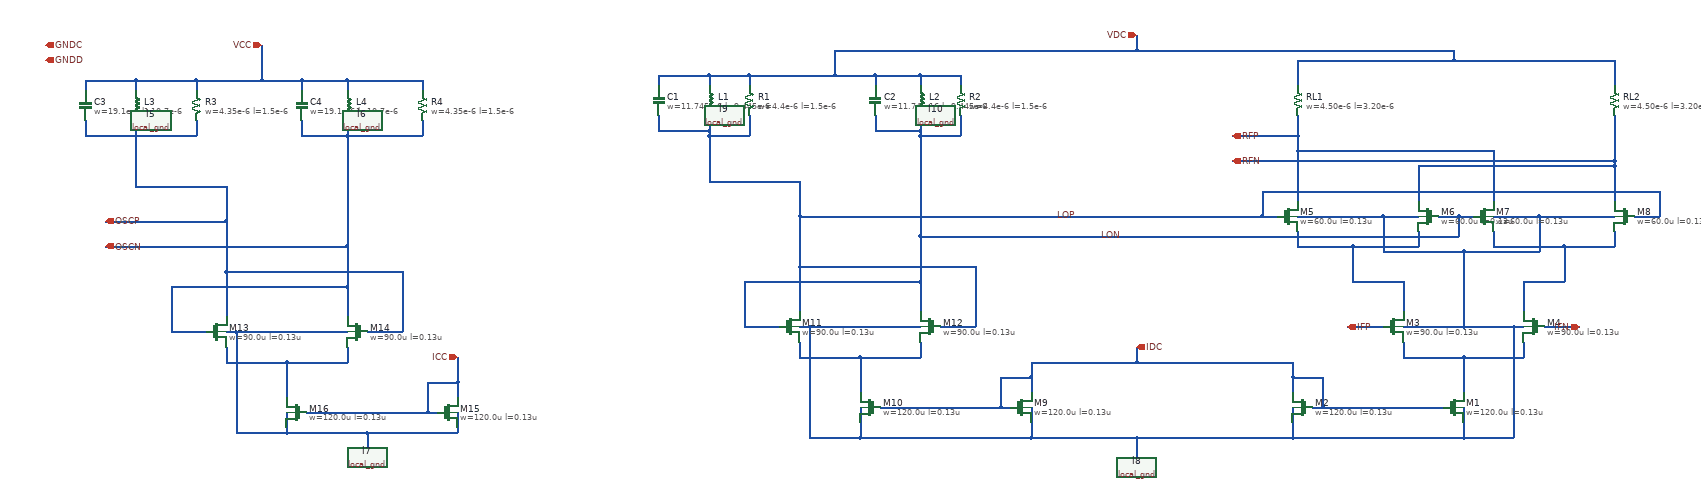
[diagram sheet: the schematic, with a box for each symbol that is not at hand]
v {xschem version=3.4.8RC file_version=1.3}
G {}
K {}
V {}
S {}
F {}
E {}
N 2820 -540 2820 -510 {
lab=#net1}
N 2940 -510 3060 -510 {
lab=#net1}
N 3060 -540 3060 -510 {
lab=#net1}
N 2940 -510 2940 -440 {
lab=#net1}
N 2820 -510 2940 -510 {
lab=#net1}
N 2660 -410 2900 -410 {
lab=IDC}
N 2600 -410 2600 -350 {
lab=GNDD}
N 2940 -410 2940 -350 {
lab=GNDD}
N 2600 -470 2600 -440 {
lab=IDC}
N 2600 -470 2660 -470 {
lab=IDC}
N 2600 -500 2600 -470 {
lab=IDC}
N 2660 -470 2660 -410 {
lab=IDC}
N 2640 -410 2660 -410 {
lab=IDC}
N 2710 -570 2780 -570 {
lab=IFP}
N 3100 -570 3170 -570 {
lab=IFN}
N 2610 -760 2610 -730 {
lab=#net2}
N 2720 -730 2850 -730 {
lab=#net2}
N 2850 -760 2850 -730 {
lab=#net2}
N 3000 -760 3000 -730 {
lab=#net3}
N 3140 -730 3240 -730 {
lab=#net3}
N 3240 -760 3240 -730 {
lab=#net3}
N 2820 -660 2820 -600 {
lab=#net2}
N 2720 -660 2820 -660 {
lab=#net2}
N 2720 -730 2720 -660 {
lab=#net2}
N 2610 -730 2720 -730 {
lab=#net2}
N 3060 -660 3060 -600 {
lab=#net3}
N 3060 -660 3140 -660 {
lab=#net3}
N 3140 -730 3140 -660 {
lab=#net3}
N 3000 -730 3140 -730 {
lab=#net3}
N 2930 -790 2960 -790 {
lab=LON}
N 3280 -790 3330 -790 {
lab=LOP}
N 3330 -840 3330 -790 {
lab=LOP}
N 2540 -840 3330 -840 {
lab=LOP}
N 2540 -840 2540 -790 {
lab=LOP}
N 2540 -790 2570 -790 {
lab=LOP}
N 2930 -790 2930 -750 {
lab=LON}
N 2890 -790 2930 -790 {
lab=LON}
N 2610 -920 2610 -820 {
lab=RFP}
N 3240 -890 3240 -820 {
lab=RFN}
N 2850 -890 3240 -890 {
lab=RFN}
N 3240 -900 3240 -890 {
lab=RFN}
N 3000 -920 3000 -820 {
lab=RFP}
N 2610 -920 3000 -920 {
lab=RFP}
N 2610 -950 2610 -920 {
lab=RFP}
N 2610 -1100 2610 -1050 {
lab=VDC}
N 2920 -1100 3240 -1100 {
lab=VDC}
N 3240 -1100 3240 -1050 {
lab=VDC}
N 2920 -1120 2920 -1100 {
lab=VDC}
N 2610 -1100 2920 -1100 {
lab=VDC}
N 2290 -350 2290 -310 {
lab=GNDD}
N 2600 -350 2940 -350 {
lab=GNDD}
N 3040 -570 3060 -570 {
lab=GNDD}
N 2780 -790 2850 -790 {
lab=GNDD}
N 3090 -790 3240 -790 {
lab=GNDD}
N 3040 -570 3040 -350 {
lab=GNDD}
N 2940 -570 3040 -570 {
lab=GNDD}
N 2940 -350 3040 -350 {
lab=GNDD}
N 2780 -790 2780 -720 {
lab=GNDD}
N 2610 -790 2780 -790 {
lab=GNDD}
N 2940 -720 3090 -720 {
lab=GNDD}
N 3090 -790 3090 -720 {
lab=GNDD}
N 3000 -790 3090 -790 {
lab=GNDD}
N 2940 -720 2940 -570 {
lab=GNDD}
N 2780 -720 2940 -720 {
lab=GNDD}
N 2820 -570 2940 -570 {
lab=GNDD}
N 1860 -540 1860 -510 {
lab=#net4}
N 1620 -510 1740 -510 {
lab=#net4}
N 1620 -540 1620 -510 {
lab=#net4}
N 1740 -510 1740 -440 {
lab=#net4}
N 1740 -510 1860 -510 {
lab=#net4}
N 1780 -410 2020 -410 {
lab=IDC}
N 2080 -410 2080 -350 {
lab=GNDD}
N 1740 -410 1740 -350 {
lab=GNDD}
N 2080 -470 2080 -440 {
lab=IDC}
N 2020 -470 2080 -470 {
lab=IDC}
N 2080 -500 2080 -470 {
lab=IDC}
N 2020 -470 2020 -410 {
lab=IDC}
N 2020 -410 2040 -410 {
lab=IDC}
N 1620 -570 1640 -570 {
lab=GNDD}
N 1740 -350 2080 -350 {
lab=GNDD}
N 1640 -570 1640 -350 {
lab=GNDD}
N 1640 -570 1860 -570 {
lab=GNDD}
N 1640 -350 1740 -350 {
lab=GNDD}
N 2290 -500 2600 -500 {
lab=IDC}
N 1510 -570 1580 -570 {
lab=LON}
N 1510 -660 1510 -570 {
lab=LON}
N 1510 -660 1860 -660 {
lab=LON}
N 1620 -690 1620 -600 {
lab=LOP}
N 1860 -660 1860 -600 {
lab=LON}
N 1900 -570 1970 -570 {
lab=LOP}
N 1970 -690 1970 -570 {
lab=LOP}
N 1620 -690 1970 -690 {
lab=LOP}
N 1620 -790 1620 -690 {
lab=LOP}
N 1860 -750 1860 -660 {
lab=LON}
N 1340 -990 1340 -960 {
lab=LOP}
N 1340 -1070 1340 -1050 {
lab=VDC}
N 1620 -860 1620 -790 {
lab=LOP}
N 1440 -860 1620 -860 {
lab=LOP}
N 1440 -950 1440 -860 {
lab=LOP}
N 1340 -960 1440 -960 {
lab=LOP}
N 1770 -1070 1770 -1050 {
lab=VDC}
N 1770 -990 1770 -960 {
lab=LON}
N 1860 -950 1860 -750 {
lab=LON}
N 1770 -960 1860 -960 {
lab=LON}
N 1690 -1070 1770 -1070 {
lab=VDC}
N 1690 -1120 1690 -1070 {
lab=VDC}
N 2290 -1150 2290 -1120 {
lab=VDC}
N 2290 -1120 2920 -1120 {
lab=VDC}
N 2480 -950 2610 -950 {
lab=RFP}
N 2610 -990 2610 -950 {
lab=RFP}
N 2850 -890 2850 -820 {
lab=RFN}
N 2480 -900 3240 -900 {
lab=RFN}
N 3240 -990 3240 -900 {
lab=RFN}
N 1520 -1070 1690 -1070 {
lab=VDC}
N 720 -530 720 -500 {
lab=#net5}
N 480 -500 600 -500 {
lab=#net5}
N 480 -530 480 -500 {
lab=#net5}
N 600 -500 600 -430 {
lab=#net5}
N 600 -500 720 -500 {
lab=#net5}
N 640 -400 880 -400 {
lab=ICC}
N 940 -460 940 -430 {
lab=ICC}
N 880 -460 940 -460 {
lab=ICC}
N 880 -460 880 -400 {
lab=ICC}
N 880 -400 900 -400 {
lab=ICC}
N 480 -560 500 -560 {
lab=GNDC}
N 500 -560 720 -560 {
lab=GNDC}
N 370 -560 440 -560 {
lab=OSCN}
N 370 -650 370 -560 {
lab=OSCN}
N 370 -650 720 -650 {
lab=OSCN}
N 480 -680 480 -590 {
lab=OSCP}
N 720 -650 720 -590 {
lab=OSCN}
N 760 -560 830 -560 {
lab=OSCP}
N 830 -680 830 -560 {
lab=OSCP}
N 480 -680 830 -680 {
lab=OSCP}
N 200 -980 200 -950 {
lab=OSCP}
N 420 -980 420 -950 {
lab=OSCP}
N 200 -1060 200 -1040 {
lab=VCC}
N 420 -1060 420 -1040 {
lab=VCC}
N 480 -780 480 -680 {
lab=OSCP}
N 300 -850 480 -850 {
lab=OSCP}
N 300 -950 300 -850 {
lab=OSCP}
N 200 -950 300 -950 {
lab=OSCP}
N 630 -1060 630 -1040 {
lab=VCC}
N 870 -1060 870 -1040 {
lab=VCC}
N 720 -1060 870 -1060 {
lab=VCC}
N 630 -980 630 -950 {
lab=OSCN}
N 870 -980 870 -950 {
lab=OSCN}
N 720 -950 870 -950 {
lab=OSCN}
N 720 -730 720 -650 {
lab=OSCN}
N 630 -950 720 -950 {
lab=OSCN}
N 550 -1060 630 -1060 {
lab=VCC}
N 420 -1060 550 -1060 {
lab=VCC}
N 300 -1060 420 -1060 {
lab=VCC}
N 300 -950 420 -950 {
lab=OSCP}
N 720 -950 720 -730 {
lab=OSCN}
N 550 -1130 550 -1060 {
lab=VCC}
N 240 -780 480 -780 {
lab=OSCP}
N 480 -850 480 -780 {
lab=OSCP}
N 240 -730 720 -730 {
lab=OSCN}
N 940 -510 940 -460 {
lab=ICC}
N 500 -560 500 -360 {
lab=GNDC}
N 500 -360 600 -360 {
lab=GNDC}
N 600 -400 600 -360 {
lab=GNDC}
N 760 -360 940 -360 {
lab=GNDC}
N 940 -400 940 -360 {
lab=GNDC}
N 760 -360 760 -330 {
lab=GNDC}
N 600 -360 760 -360 {
lab=GNDC}
N 300 -980 300 -950 {
lab=OSCP}
N 300 -1060 300 -1040 {
lab=VCC}
N 200 -1060 300 -1060 {
lab=VCC}
N 1440 -1070 1440 -1050 {
lab=VDC}
N 1340 -1070 1440 -1070 {
lab=VDC}
N 1440 -990 1440 -960 {
lab=LOP}
N 1860 -1070 1860 -1050 {
lab=VDC}
N 1770 -1070 1860 -1070 {
lab=VDC}
N 1860 -990 1860 -960 {
lab=LON}
N 720 -1060 720 -1040 {
lab=VCC}
N 630 -1060 720 -1060 {
lab=VCC}
N 720 -980 720 -950 {
lab=OSCN}
N 1860 -750 2930 -750 {
lab=LON}
N 1620 -790 2540 -790 {
lab=LOP}
N 1520 -1070 1520 -1050 {
lab=VDC}
N 1440 -1070 1520 -1070 {
lab=VDC}
N 1520 -990 1520 -950 {
lab=LOP}
N 1440 -950 1520 -950 {
lab=LOP}
N 1440 -960 1440 -950 {
lab=LOP}
N 1940 -1070 1940 -1050 {
lab=VDC}
N 1860 -1070 1940 -1070 {
lab=VDC}
N 1940 -990 1940 -950 {
lab=LON}
N 1860 -950 1940 -950 {
lab=LON}
N 1860 -960 1860 -950 {
lab=LON}
N 1690 -1120 2290 -1120 {
lab=VDC}
N 2290 -350 2600 -350 {
lab=GNDD}
N 2290 -530 2290 -500 {
lab=IDC}
N 2080 -500 2290 -500 {
lab=IDC}
N 2080 -350 2290 -350 {
lab=GNDD}
C {sg13g2_pr/sg13_lv_nmos.sym} 2870 -790 0 1 {name=M6
l=0.13u
w=60.0u
ng=10
m=1
model=sg13_lv_nmos
spiceprefix=X
lvs_format="@spiceprefix@name @pinlist @model w=@w l=@l ng=@ng m=@m"}
C {sg13g2_pr/rppd.sym} 3240 -1020 0 0 {name=RL2
w=4.50e-6
l=3.20e-6
model=rppd
spiceprefix=X
b=0
m=1
lvs_format="@spiceprefix@name @pinlist @model w=@w l=@l m=@m b=@b"
}
C {sg13g2_pr/rppd.sym} 2610 -1020 0 0 {name=RL1
w=4.50e-6
l=3.20e-6
model=rppd
spiceprefix=X
b=0
m=1
lvs_format="@spiceprefix@name @pinlist @model w=@w l=@l m=@m b=@b"
}
C {sg13g2_pr/sg13_lv_nmos.sym} 3260 -790 0 1 {name=M8
l=0.13u
w=60.0u
ng=10
m=1
model=sg13_lv_nmos
spiceprefix=X
lvs_format="@spiceprefix@name @pinlist @model w=@w l=@l ng=@ng m=@m"}
C {sg13g2_pr/sg13_lv_nmos.sym} 2980 -790 0 0 {name=M7
l=0.13u
w=60.0u
ng=10
m=1
model=sg13_lv_nmos
spiceprefix=X
lvs_format="@spiceprefix@name @pinlist @model w=@w l=@l ng=@ng m=@m"}
C {sg13g2_pr/sg13_lv_nmos.sym} 2590 -790 0 0 {name=M5
l=0.13u
w=60.0u
ng=10
m=1
model=sg13_lv_nmos
spiceprefix=X
lvs_format="@spiceprefix@name @pinlist @model w=@w l=@l ng=@ng m=@m"}
C {sg13g2_pr/sg13_lv_nmos.sym} 3080 -570 0 1 {name=M4
l=0.13u
w=90.0u
ng=15
m=1
model=sg13_lv_nmos
spiceprefix=X
lvs_format="@spiceprefix@name @pinlist @model w=@w l=@l ng=@ng m=@m"}
C {sg13g2_pr/sg13_lv_nmos.sym} 2800 -570 0 0 {name=M3
l=0.13u
w=90.0u
ng=15
m=1
model=sg13_lv_nmos
spiceprefix=X
lvs_format="@spiceprefix@name @pinlist @model w=@w l=@l ng=@ng m=@m"}
C {sg13g2_pr/sg13_lv_nmos.sym} 2620 -410 0 1 {name=M2
l=0.13u
w=120.0u
ng=20
m=1
model=sg13_lv_nmos
spiceprefix=X
lvs_format="@spiceprefix@name @pinlist @model w=@w l=@l ng=@ng m=@m"}
C {sg13g2_pr/sg13_lv_nmos.sym} 2920 -410 0 0 {name=M1
l=0.13u
w=120.0u
ng=20
m=1
model=sg13_lv_nmos
spiceprefix=X
lvs_format="@spiceprefix@name @pinlist @model w=@w l=@l ng=@ng m=@m"}
C {iopin.sym} 2480 -900 0 1 {name=p4 lab=RFN}
C {iopin.sym} 2480 -950 0 1 {name=p5 lab=RFP}
C {iopin.sym} 2290 -1150 3 0 {name=p6 lab=VDC}
C {iopin.sym} 2710 -570 0 1 {name=p1 lab=IFP}
C {iopin.sym} 3170 -570 0 0 {name=p7 lab=IFN}
C {iopin.sym} 2290 -530 1 1 {name=p9 lab=IDC
}
C {sg13g2_pr/sg13_lv_nmos.sym} 1600 -570 0 0 {name=M11
l=0.13u
w=90.0u
ng=15
m=1
model=sg13_lv_nmos
spiceprefix=X
lvs_format="@spiceprefix@name @pinlist @model w=@w l=@l ng=@ng m=@m"}
C {sg13g2_pr/sg13_lv_nmos.sym} 1880 -570 0 1 {name=M12
l=0.13u
w=90.0u
ng=15
m=1
model=sg13_lv_nmos
spiceprefix=X
lvs_format="@spiceprefix@name @pinlist @model w=@w l=@l ng=@ng m=@m"}
C {sg13g2_pr/sg13_lv_nmos.sym} 2060 -410 0 0 {name=M9
l=0.13u
w=120.0u
ng=20
m=1
model=sg13_lv_nmos
spiceprefix=X
lvs_format="@spiceprefix@name @pinlist @model w=@w l=@l ng=@ng m=@m"}
C {sg13g2_pr/sg13_lv_nmos.sym} 1760 -410 0 1 {name=M10
l=0.13u
w=120.0u
ng=20
m=1
model=sg13_lv_nmos
spiceprefix=X
lvs_format="@spiceprefix@name @pinlist @model w=@w l=@l ng=@ng m=@m"}
C {sg13g2_pr/cap_cmim.sym} 1340 -1020 0 0 {name=C1
model=cap_cmim
w=11.745e-6
l=9.445e-6
m=1
spiceprefix=X}
C {sg13g2_pr/rppd.sym} 1520 -1020 0 0 {name=R1
w=4.4e-6
l=1.5e-6
model=rppd
spiceprefix=X
b=0
m=1
lvs_format="@spiceprefix@name @pinlist @model w=@w l=@l m=@m b=@b"
}
C {sg13g2_pr/cap_cmim.sym} 1770 -1020 0 0 {name=C2
model=cap_cmim
w=11.745e-6
l=9.445e-6
m=1
spiceprefix=X}
C {sg13g2_pr/rppd.sym} 1940 -1020 0 0 {name=R2
w=4.4e-6
l=1.5e-6
model=rppd
spiceprefix=X
b=0
m=1
lvs_format="@spiceprefix@name @pinlist @model w=@w l=@l m=@m b=@b"
}
C {sg13g2_pr/sg13_lv_nmos.sym} 460 -560 0 0 {name=M13
l=0.13u
w=90.0u
ng=15
m=1
model=sg13_lv_nmos
spiceprefix=X
lvs_format="@spiceprefix@name @pinlist @model w=@w l=@l ng=@ng m=@m"}
C {sg13g2_pr/sg13_lv_nmos.sym} 740 -560 0 1 {name=M14
l=0.13u
w=90.0u
ng=15
m=1
model=sg13_lv_nmos
spiceprefix=X
lvs_format="@spiceprefix@name @pinlist @model w=@w l=@l ng=@ng m=@m"}
C {sg13g2_pr/sg13_lv_nmos.sym} 920 -400 0 0 {name=M15
l=0.13u
w=120.0u
ng=20
m=1
model=sg13_lv_nmos
spiceprefix=X
lvs_format="@spiceprefix@name @pinlist @model w=@w l=@l ng=@ng m=@m"}
C {sg13g2_pr/sg13_lv_nmos.sym} 620 -400 0 1 {name=M16
l=0.13u
w=120.0u
ng=20
m=1
model=sg13_lv_nmos
spiceprefix=X
lvs_format="@spiceprefix@name @pinlist @model w=@w l=@l ng=@ng m=@m"}
C {sg13g2_pr/cap_cmim.sym} 200 -1010 0 0 {name=C3
model=cap_cmim
w=19.1e-6
l=10.7e-6
m=1
spiceprefix=X}
C {sg13g2_pr/rppd.sym} 420 -1010 0 0 {name=R3
w=4.35e-6
l=1.5e-6
model=rppd
spiceprefix=X
b=0
m=1
lvs_format="@spiceprefix@name @pinlist @model w=@w l=@l m=@m b=@b"
}
C {sg13g2_pr/cap_cmim.sym} 630 -1010 0 0 {name=C4
model=cap_cmim
w=19.1e-6
l=10.7e-6
m=1
spiceprefix=X}
C {sg13g2_pr/rppd.sym} 870 -1010 0 0 {name=R4
w=4.35e-6
l=1.5e-6
model=rppd
spiceprefix=X
b=0
m=1
lvs_format="@spiceprefix@name @pinlist @model w=@w l=@l m=@m b=@b"
}
C {iopin.sym} 240 -730 0 1 {name=p2 lab=OSCN}
C {iopin.sym} 240 -780 0 1 {name=p3 lab=OSCP}
C {iopin.sym} 550 -1130 3 0 {name=p10 lab=VCC}
C {iopin.sym} 940 -510 3 0 {name=p11 lab=ICC}
C {lab_wire.sym} 2170 -790 0 0 {name=p15 sig_type=std_logic lab=LOP
}
C {lab_wire.sym} 2260 -750 0 0 {name=p13 sig_type=std_logic lab=LON
}
C {inductor2.sym} 1440 -1020 0 0 {name=L1
m=1
value=1n
footprint=1206
device=inductor2
spiceprefix=X
w=10u
s=10u
d=222u
nr_r=2
}
C {inductor2.sym} 1860 -1020 0 0 {name=L2
m=1
value=1n
footprint=1206
device=inductor2
spiceprefix=X
w=10u
s=10u
d=222u
nr_r=2
}
C {inductor2.sym} 300 -1010 0 0 {name=L3
m=1
value=1n
footprint=1206
device=inductor2
spiceprefix=X
w=10u
s=10u
d=222u
nr_r=2}
C {inductor2.sym} 720 -1010 0 0 {name=L4
m=1
value=1n
footprint=1206
device=inductor2
spiceprefix=X
w=10u
s=10u
d=222u
}
C {iopin.sym} 120 -1130 0 1 {name=p19 lab=GNDC}
C {local_gnd.sym} 330 -980 0 0 {name=l5 lab=GNDC}
C {local_gnd.sym} 750 -980 0 0 {name=l6 lab=GNDC}
C {local_gnd.sym} 760 -330 0 0 {name=l7 lab=GNDC}
C {local_gnd.sym} 2290 -310 0 0 {name=l8 lab=GNDD}
C {local_gnd.sym} 1470 -990 0 0 {name=l9 lab=GNDD}
C {local_gnd.sym} 1890 -990 0 0 {name=l10 lab=GNDD}
C {title.sym} 280 -90 0 0 {name=T1 author="H. Ojiro"}
C {iopin.sym} 120 -1100 0 1 {name=p8 lab=GNDD}
